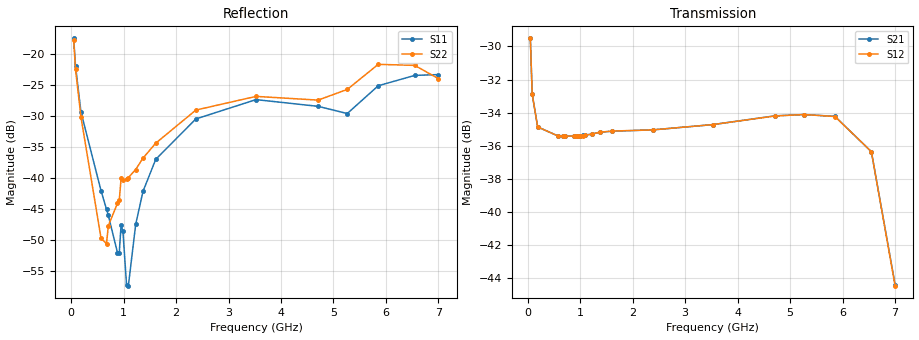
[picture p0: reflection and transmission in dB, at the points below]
! Integrated Device Technology
! Corporate Headquarters
! 6024 Silver Creek Valley Road
! San Jose, CA 95138  USA
! Phone:  1-408-284-8200
! Toll Free:  1-800-223-1366
! Webpage:  http://www.idt.com/
! Timing and RF Division
! 515 Groton Road, Suite 102
! Westford, MA 01886-6024
! Device:  F2258
! Description: Voltage Variable RF Attenuator
! Frequency:  50.0 -  6000.00 MHz
! Package:  3x3 mm Thin QFN Plastic Package: 16 pin
! Ports:  2 RF, 2 DC
!  Pin  1  = NC
!  Pin  2  = NC
!  Pin  3  = RF2  = Port 2
!  Pin  4  = GND
!  Pin  5  = Vdd
!  Pin  6  = NC
!  Pin  7  = VCTRL
!  Pin  8  = NC
!  Pin  9  = GND
!  Pin 10  = RF1  = Port 1
!  Pin 11  = NC
!  Pin 12  = NC
!  Pin 13  = NC
!  Pin 14  = NC
!  Pin 15  = NC
!  Pin 16  = NC
! Vcntrl:  2.260 Volts
! Vdd:  +3.300 Volts
! Current:  1.148 mA
! Data:  The device was measured on a the F2258 evaluation board which has
!  individual transmission lines to the RF pins.  Data was collected
!  using a calibrated network analyzer.  The evaluation board was
!  de-embedded using a TRL calibration technique.
!  The reference plane is the edge of the package pin.
! Misc:  SN 10
!  Action Tracker AT0285
! Date Measured:  2014-12-10
! Date:  2016-01-13  MJV
! Note:
!  Integrated Device Technology supplies this data as a sample of measured
!  data at the package pin for this product.  Your particular data for this
!  product may vary.
!  Data was taken at 25 degrees C.
!  Integrated Device Technology reserves the right to change this data at anytime.
!Freq_(GHz)  S11M_(dB)  S11P_(deg)  S21M_(dB)  S21P_(deg)  S12M_(dB)  S12P_(deg)  S22M_(dB)  S22P_(deg)
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# GHz S dB R 50
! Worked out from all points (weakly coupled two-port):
!   201 points, 50 MHz to 7 GHz, reference 50 ohm
!   highest |S21| = -29.51 dB at 50 MHz (marker M1); lowest = -44.4 dB at 7 GHz (marker M2)
!   lowest |S11| = -57.4 dB at 1.093 GHz (marker M3), VSWR 1.00, Z = 49.9 + j0.115 ohm
!   |S11| at or under -10 dB: start of sweep to end of sweep
!   |S22| runs from -50.9 to -17.9 dB; largest |S21 - S12| = 9e-05
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0.05  -17.55 -111.0  -29.51 -68.4  -29.51 -68.4  -17.86 -111.2
0.08475  -21.98 -107.4  -32.87 -48.7  -32.87 -48.7  -22.54 -107.3
0.189  -29.42 -109.4  -34.87 -24.7  -34.87 -24.7  -30.22 -109.1
0.57125  -42.07 -124.9  -35.41 -10.3  -35.41 -10.4  -49.72 -161.3
0.6755  -45.06 -132.2  -35.42 -9.4  -35.42 -9.4  -50.61 141.6
0.71025  -46.05 -137.2  -35.42 -9.2  -35.43 -9.2  -47.70 131.1
0.884  -52.03 165.6  -35.42 -8.4  -35.42 -8.4  -44.12 114.3
0.91875  -52.02 150.0  -35.41 -8.3  -35.41 -8.3  -43.59 112.7
0.9535  -47.59 -163.2  -35.43 -8.2  -35.42 -8.2  -40.10 120.2
0.98825  -48.59 -174.2  -35.41 -8.1  -35.41 -8.1  -40.42 117.5
1.05775  -57.28 153.7  -35.38 -8.0  -35.39 -8.0  -40.22 102.6
1.0925  -57.36 121.7  -35.37 -7.9  -35.37 -7.9  -39.95 98.7
1.2315  -47.50 46.6  -35.30 -7.9  -35.30 -7.9  -38.66 77.3
1.3705  -42.18 37.2  -35.19 -8.4  -35.19 -8.4  -36.83 64.9
1.61375  -37.02 32.9  -35.13 -9.6  -35.12 -9.6  -34.42 52.0
2.37825  -30.52 48.2  -35.05 -13.2  -35.05 -13.2  -29.09 42.7
3.525  -27.41 91.6  -34.73 -19.7  -34.73 -19.6  -26.89 67.0
4.7065  -28.49 95.7  -34.20 -28.8  -34.21 -28.8  -27.49 58.3
5.2625  -29.65 54.3  -34.12 -34.9  -34.12 -34.9  -25.77 20.9
5.85325  -25.18 29.9  -34.23 -45.5  -34.24 -45.6  -21.73 -2.7
6.54825  -23.51 45.0  -36.37 -66.3  -36.37 -66.4  -21.90 -37.8
7  -23.38 84.4  -44.41 -61.8  -44.48 -61.0  -24.03 -129.8
